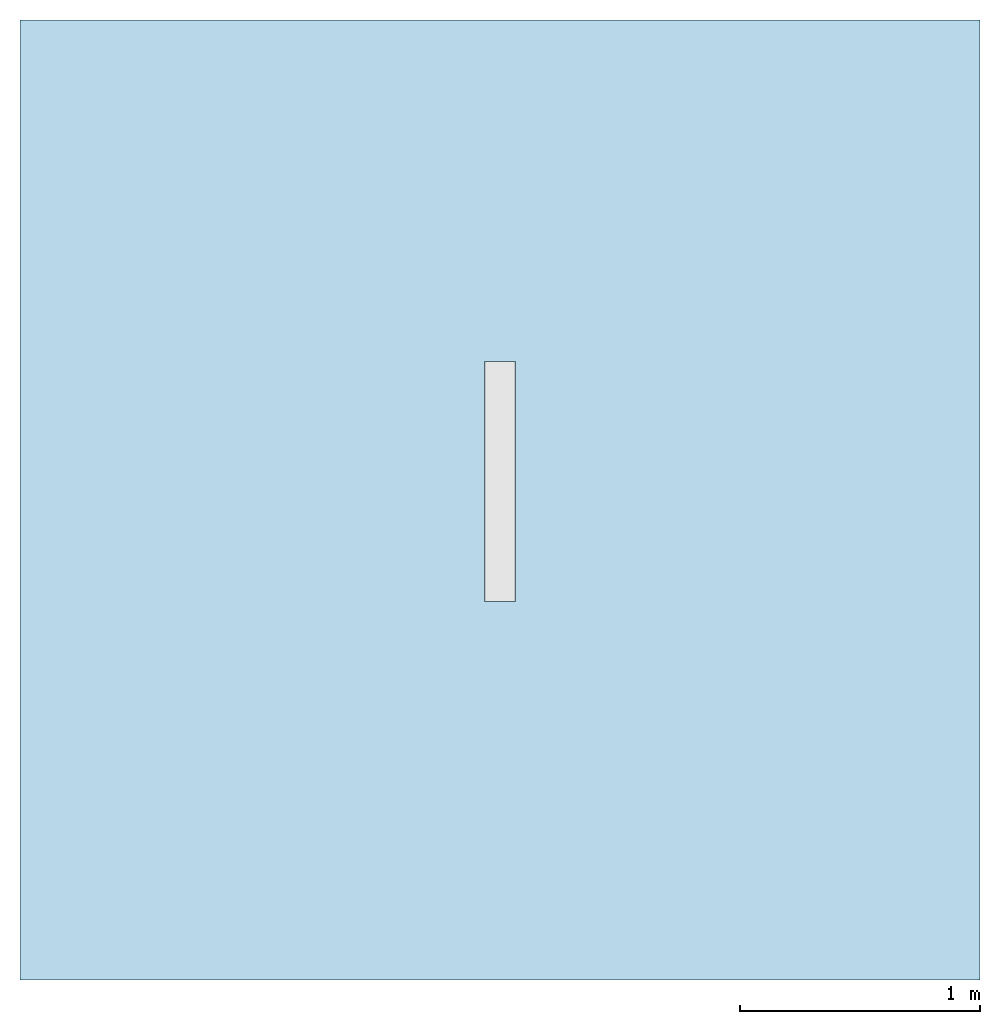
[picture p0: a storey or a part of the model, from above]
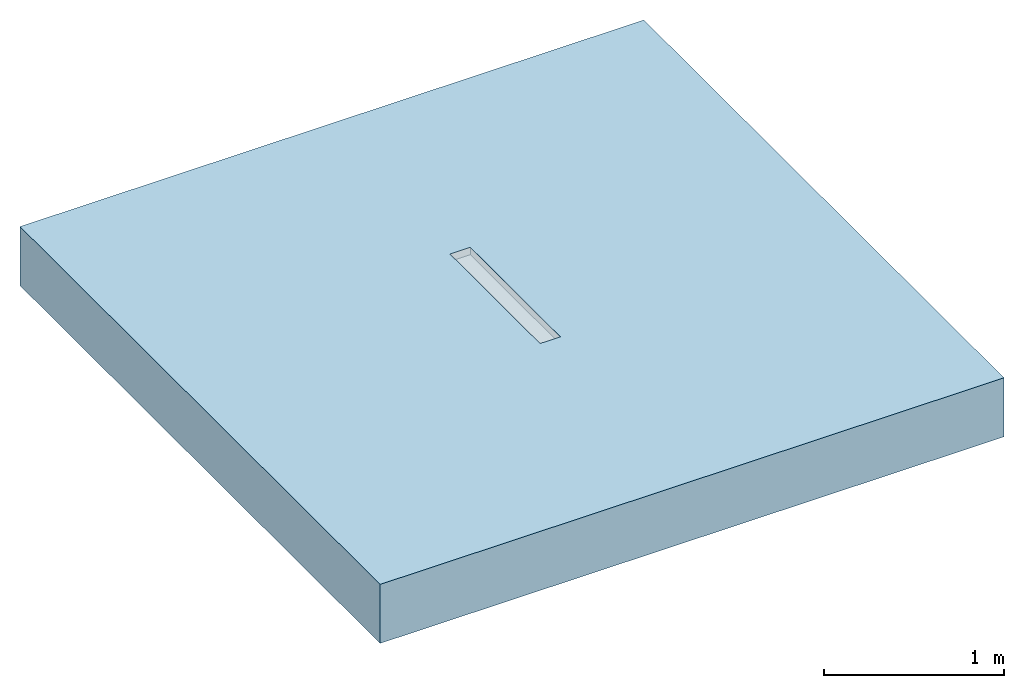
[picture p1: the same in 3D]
Properties of the parts of a building model (IFC2X3)

# File
Description: ViewDefinition [CoordinationView]
File name: Project Number
Time: 2014-06-06T15:12:34
Written by: The EXPRESS Data Manager Version 5.01.0100.02.64mod : 6 Jun 2012
Made in: 20130308_1515(x64) - Exporter 2014.0.2013.0308 - Default UI
Comment: STEP Physical File produced by: The EXPRESS Data Manager Version 5.01.0100.02.64mod : 6 Jun 2012 * Module: EDMstepFileFactory/EDMstandAlone * Creation date: Fri Jun 06 15:12:34 2014 * Host: IN-BLR-PC-0010 * Database: C:\Users\palleri\AppData\Local\Temp\{614CE540-728E-48EB-9BE4-249267B4F069}\ifc * Database version: 5507 * Database creation date: Fri Jun 06 15:12:32 2014 * Schema: IFC2X3 * Model: DataRepository.ifc * Model creation date: Fri Jun 06 15:12:33 2014 * Header model: DataRepository.ifc_HeaderModel * Header model creation date: Fri Jun 06 15:12:33 2014 * EDMuser: sdai-user * EDMgroup: sdai-group * License ID and type: 5605 : Permanent license. Expiry date: * EDMstepFileFactory options: 020000

# IfcProject, Project Number
LongName: Project Name; Phase: Project Status

# IfcSite, Default
RefLatitude: 42, 21, 30, 344238; RefLongitude: -71, -3, -35, -194702; RefElevation: 0 mm

# IfcBuilding
Pset_BuildingCommon - NumberOfStoreys: 1
Other - Project Name: Project Name; Project Number: Project Number; Project Issue Date: Issue Date; Project Address: ## Street City, State Zip; Client Name: Owner; Project Status: Project Status

# IfcBuildingStorey, Level 1
LongName: Level 1; Elevation: 0 mm
Constraints - Elevation Base: Project Base Point; Elevation: 0 mm
Graphics - Line Pattern: Center; Symbol at End 1 Default: no; Symbol at End 2 Default: yes; Color: 0; Line Weight: 1; Symbol: M_Level Head - Circle: M_Level Head - Circle
Identity Data - Structural: no; Building Story: yes; Name: Level 1
Dimensions - Computation Height: 0 mm

# IfcFlowTerminal: 38221 - Fixed Height Channel - Shallow Section - 1000mm LG - Invert Depth 50mm, ACO Freedeck Fixed Height Channel Shallow Section - Stainless Steel:38221 - Fixed Height Channel - Shallow Section - 1000mm LG - Invert Depth 50mm:312361
In: Level 1
Material: Stainless Steel Grade 304
Construction - 36952 - Grating - Plain Mesh - Galvanised Steel - 500mm long: no; 00276 - Grating - Slotted Grating - Galvanised Steel - 1000mm long: no; End Plate Invert 1: no; 36954 - Grating - Plain Mesh - Stainless Steel 304 - 500mm long: no; 00277 - Grating - Slotted Grating - Galvanised Steel - 500mm long: no; 00272 - Grating - Slotted Grating - Stainless Steel 304 - 1000mm long: no; End Plate Invert 2: no; 00273 - Grating - Slotted Grating - Stainless Steel 304 - 500mm long: no; 36953 - Grating - Plain Mesh - Galvanised Steel - 1000mm long: no; 36955 - Grating - Plain Mesh - Stainless Steel 304 - 1000mm long: yes
Constraints - Moves With Nearby Elements: no; Level: Level: Level 1
Identity Data - Mark: 29; E-mail Technical: abdtechnical@aco.co.uk; E-mail Sales: abdcommercial@aco.co.uk; Watermarked By: www.acobd.com; Fax: +44 (0)1462 851490; Website: www.acobd.com; Address: ACO Business Centre, Caxton Road, Bedford, MK41 0LF; Watermark2: This file is water marked and users are prohibited to reproduce, adapt, distribute this information; Watermark1: This file is the property of ACO Technologies PLC; Manufacturer: ACO Building Drainage; Watermarked With: BIM Manager Premium Suite; Telephone: +44 (0)1462 816666
Phasing - Phase Created: New Construction
Pset_ManufacturerTypeInformation - Manufacturer: ACO Building Drainage
General - Channel Recycled Material Content: 60-70%; Product Code: 38221; Channel Material: Stainless Steel Grade 304; Product Description: ACO FreeDeck Fixed Height Channel - Shallow Section; Channel Recyclable: Fully recyclable; Product Range: ACO Freedeck; Maintenance Guidelines: X:\Electronic Literature\ABD Electronic Literature\Roof and Balcony Drainage\ACO Freedeck Brochure.pdf; Weight (Kg): 2.0kg; Product Standard: BS EN 1433:2002, CE marked; Installation Guidelines: X:\Electronic Literature\ABD Electronic Literature\Roof and Balcony Drainage\ACO Freedeck Brochure.pdf; Dimensions (LxWxH): 1000 x 130 x 50; Product Type: Linear Deck Drainage System; Price: POA - contact ACO; Load Class: A15; Channel Colour: Mid Grey; NBS Specification: NBS Section R10 Gravity Rainwater Drainage Systems, Subsection 365
Model Properties - End Plate Product Code 38223: End Plate - Stainless Steel for Invert Depth - 50mm - 0.1Kg; Grating Product Code 36954: Load Class A15 - Mesh Grating - 14mm x 30mm Mesh - Stainless Steel 304 - 500mm long - 1.6kg; Grating Product Code 00273: Load Class A15 - Slotted Grating - 10 x 80mm Slot - Stainless Steel 304 - 500mm long - 1.0kg; Grating Product Code 00272: Load Class A15 - Slotted Grating - 10 x 80mm Slot - Stainless Steel 304 - 1000mm long - 2.2kg; Grating Product Code 36955: Load Class A15 - Mesh Grating - 14mm x 30mm Mesh - Stainless Steel 304 - 1000mm long - 3.0kg
Dimensions - Height: 50 mm; Grating End Length: 1000 mm; Channel End Length: -1000 mm
Other - Nos: 32
Materials and Finishes - Material: Stainless Steel Grade 304

# IfcSlab: Floor:Generic Floor - 400mm, Floor:Generic Floor - 400mm:193825
In: Level 1
PredefinedType: FLOOR; Material: Concrete, Broom Finish 400 mm
Dimensions - Area: 16 m2; Volume: 6.3935 m3; Thickness: 400 mm; Perimeter: 16000 mm
Constraints - Related to Mass: no; Level: Level: Level 1; Height Offset From Level: 0 mm; Room Bounding: yes
Structural - Enable Analytical Model: no; Structural: no
Phasing - Phase Created: New Construction
Pset_SlabCommon - Reference: Generic Floor - 400mm; IsExternal: no; LoadBearing: yes; ThermalTransmittance: 2.615 kg/K/s3; PitchAngle: 0 deg
Construction - Function: Interior; Default Thickness: 400 mm
Analytical Properties - Heat Transfer Coefficient (U): 2.615; Thermal mass: 604440; Roughness: 1; Absorptance: 0.1; Thermal Resistance (R): 0.382409
Materials and Finishes - Structural Material: Concrete, Broom Finish
Graphics - Coarse Scale Fill Color: 0
